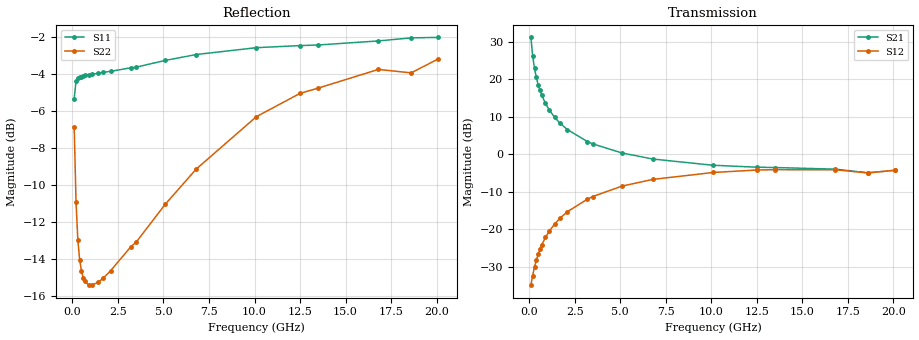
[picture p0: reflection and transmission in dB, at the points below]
!  Infineon Technologies AG
! BFR380L3 , PF131585-7, No.6, Th 09.10.01, soldered on pcb-board, measured with PP GSG850
!  Vce=1.5 V,  Ic=75.0 mA
! Common Emitter S-Parameters:  15. November 2001
#  GHz  S  MA  R  50
! f  S11  S21  S12  S22
! GHz  Mag  Ang  Mag  Ang  Mag  Ang  Mag  Ang
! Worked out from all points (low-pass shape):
!   201 points, 100 MHz to 20.1 GHz, reference 50 ohm
!   highest |S21| = 31.12 dB at 100 MHz (marker M1); lowest = -5.0 dB at 18.6 GHz (marker M2)
!   |S21| within 3 dB of the highest: start of sweep to 160.1 MHz
!   lowest |S11| = -5.4 dB at 100 MHz (marker M3), VSWR 3.34, Z = 17.6 - j19.9 ohm
!   |S11| at or under -10 dB: nowhere
!   |S22| runs from -15.4 to -3.2 dB; largest |S21 - S12| = 36
!   S11 on the Smith chart (normalised r, x): 100 MHz: 0.35, -0.40; 600 MHz: 0.23, -0.00; 3.2 GHz: 0.24, +0.37; 6.8 GHz: 0.29, +0.83; 12.5 GHz: 0.52, +1.56; 20.1 GHz: 1.03, +2.61
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0.1  0.5395 -132.0  35.96 121.0  0.01797 52.9  0.452 -73.7
0.2  0.6029 -157.1  20.24 104.4  0.02408 58.3  0.2847 -102.6
0.3  0.6139 -166.6  13.86 97.3  0.03156 62.6  0.2246 -119.0
0.4  0.617 -172.5  10.51 92.8  0.0387 65.6  0.1985 -130.2
0.5  0.6191 -176.4  8.452 89.4  0.04614 68.0  0.1852 -138.2
0.6  0.6228 -179.8  7.067 86.7  0.05408 69.2  0.1775 -144.1
0.7  0.6255 177.5  6.079 84.2  0.06185 69.8  0.1738 -148.8
0.9  0.6263 173.0  4.754 79.9  0.07748 70.7  0.1698 -155.5
1.1  0.6288 169.2  3.917 76.1  0.09327 70.5  0.1703 -160.1
1.4  0.6317 163.8  3.105 70.8  0.1166 69.6  0.1726 -165.2
1.7  0.6359 158.9  2.583 65.9  0.1401 68.1  0.1774 -169.1
2.1  0.6399 152.7  2.127 59.6  0.1705 65.7  0.1857 -173.2
3.2  0.6541 137.2  1.473 44.5  0.2509 57.8  0.2152 176.6
3.5  0.6567 133.3  1.369 40.7  0.2725 55.5  0.2216 174.6
5.1  0.6848 114.5  1.037 23.5  0.3747 43.0  0.2805 159.9
6.8  0.7103 97.6  0.8599 9.9  0.4609 30.4  0.3489 143.3
10.1  0.7411 73.5  0.7111 -7.9  0.5694 8.3  0.4829 116.5
12.5  0.7508 61.5  0.6699 -18.1  0.6142 -6.3  0.5581 98.2
13.5  0.7536 57.1  0.6633 -22.1  0.6211 -12.0  0.5767 91.9
16.8  0.7728 46.0  0.6311 -33.0  0.6196 -27.1  0.6476 72.9
18.6  0.7875 43.2  0.5639 -38.6  0.5616 -33.9  0.6339 68.4
20.1  0.79 37.3  0.6091 -43.8  0.6105 -40.2  0.6915 57.9
